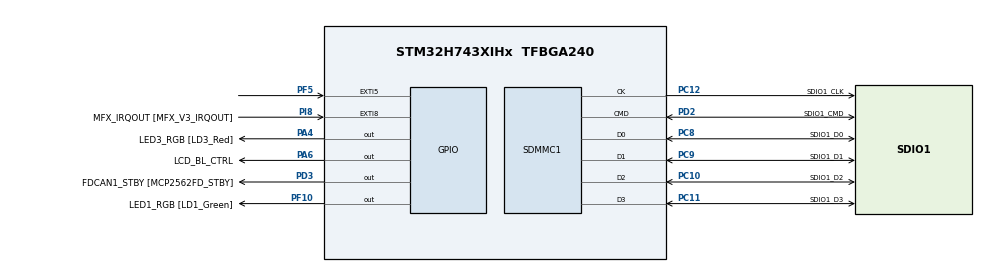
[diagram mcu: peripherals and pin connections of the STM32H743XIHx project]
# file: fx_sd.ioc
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CORTEX_M7.CPU_DCache=Enabled
CORTEX_M7.CPU_ICache=Enabled
CORTEX_M7.default_mode_Activation=1
Mcu.Family=STM32H7
Mcu.Name=STM32H743XIHx
Mcu.Package=TFBGA240
NVIC.EXTI9_5_IRQn=true\:6\:0\:true\:false\:true\:false\:true\:true\:true
NVIC.PriorityGroup=NVIC_PRIORITYGROUP_4
NVIC.SDMMC1_IRQn=true\:7\:0\:true\:false\:true\:false\:true\:true\:true
NVIC.TIM6_DAC_IRQn=true\:15\:0\:false\:false\:true\:false\:false\:true\:true
NVIC.TimeBase=TIM6_DAC_IRQn
NVIC.TimeBaseIP=TIM6
PA0_C.GPIO_Label=Potentiometer
PA0_C.Signal=ADCx_INN1
PA1.GPIO_Label=RMII_REF_CLK [LAN8742A_REFCLK0]
PA1.Signal=ETH_REF_CLK
PA10.GPIO_Label=USB_FS1_ID
PA10.Signal=USB_OTG_FS_ID
PA11.GPIO_Label=USB_FS1_DM
PA11.Signal=USB_OTG_FS_DM
PA12.GPIO_Label=USB_FS1_DP
PA12.Signal=USB_OTG_FS_DP
PA13\ (JTMS/SWDIO).GPIO_Label=TMS_SWDIO
PA13\ (JTMS/SWDIO).Signal=DEBUG_JTMS-SWDIO
PA14\ (JTCK/SWCLK).GPIO_Label=TCK_SWCLK
PA14\ (JTCK/SWCLK).Signal=DEBUG_JTCK-SWCLK
PA15\ (JTDI).GPIO_Label=TDI
PA15\ (JTDI).Signal=DEBUG_JTDI
PA2.GPIO_Label=ETH_MDIO [LAN8742A_MDIO]
PA2.Signal=ETH_MDIO
PA3.GPIO_Label=ULPI_D0 [USB3320C_D0]
PA3.Signal=USB_OTG_HS_ULPI_D0
PA4.GPIO_Label=LED3_RGB [LD3_Red]
PA4.Signal=GPIO_Output
PA5.GPIO_Label=ULPI_CK  [USB3320C_CLKOUT]
PA5.Signal=USB_OTG_HS_ULPI_CK
PA6.GPIO_Label=LCD_BL_CTRL
PA6.Signal=GPIO_Output
PA7.GPIO_Label=RMII_CRS_DV [LAN8742A_CRS_DV]
PA7.Signal=ETH_CRS_DV
PA8.GPIO_Label=MCO
PA8.Signal=RCC_MCO_1
PA9.GPIO_Label=VBUS_FS1
PA9.Signal=USB_OTG_FS_VBUS
PB0.GPIO_Label=ULPI_D1 [USB3320C_D1]
PB0.Signal=USB_OTG_HS_ULPI_D1
PB1.GPIO_Label=ULPI_D2 [USB3320C_D2]
PB1.Signal=USB_OTG_HS_ULPI_D2
PB10.GPIO_Label=ULPI_D3 [USB3320C_D3]
PB10.Signal=USB_OTG_HS_ULPI_D3
PB11.GPIO_Label=ULPI_D4 [USB3320C_D4]
PB11.Signal=USB_OTG_HS_ULPI_D4
PB12.GPIO_Label=ULPI_D5 [USB3320C_D5]
PB12.Signal=USB_OTG_HS_ULPI_D5
PB13.GPIO_Label=ULPI_D6 [USB3320C_D6]
PB13.Signal=USB_OTG_HS_ULPI_D6
PB14.GPIO_Label=RS232_TX [ST3241EBPR_T2IN]
PB14.Signal=USART1_TX
PB15.GPIO_Label=RS_232RX [ST3241EBPR_R3OUT]
PB15.Signal=USART1_RX
PB2.GPIO_Label=QSPI_CLK [MT25TL01GHBA8ESF_CLK_1]
PB2.Signal=QUADSPI_CLK
PB3\ (JTDO/TRACESWO).GPIO_Label=TDO_SWO
PB3\ (JTDO/TRACESWO).Signal=DEBUG_JTDO-SWO
PB4\ (NJTRST).GPIO_Label=TRST
PB4\ (NJTRST).Signal=DEBUG_JTRST
PB5.GPIO_Label=ULPI_D7 [USB3320C_D7]
PB5.Signal=USB_OTG_HS_ULPI_D7
PB6.GPIO_Label=I2C1_SCL [STM32L152CCT6_I2C_SCL]
PB6.Signal=I2C1_SCL
PB7.GPIO_Label=I2C1_SDA [STM32L152CCT6_I2C_SDA]
PB7.Signal=I2C1_SDA
PB8.GPIO_Label=SDIO1_CKIN
PB8.Signal=SDMMC1_CKIN
PB9.GPIO_Label=SDIO1_CDIR
PB9.Signal=SDMMC1_CDIR
PC0.GPIO_Label=ULPI_STP [USB3320C_STP]
PC0.Signal=USB_OTG_HS_ULPI_STP
PC1.GPIO_Label=RMII_MDC [LAN8742A_MDC]
PC1.Signal=ETH_MDC
PC10.GPIO_Label=SDIO1_D2
PC10.Mode=SD_4_bits_Wide_bus
PC10.Signal=SDMMC1_D2
PC11.GPIO_Label=SDIO1_D3
PC11.Mode=SD_4_bits_Wide_bus
PC11.Signal=SDMMC1_D3
PC12.GPIO_Label=SDIO1_CLK
PC12.Mode=SD_4_bits_Wide_bus
PC12.Signal=SDMMC1_CK
PC13.GPIO_Label=TAMPER_KEY [B1]
PC13.Signal=RTC_TAMP1
PC14-OSC32_IN\ (OSC32_IN).Signal=RCC_OSC32_IN
PC15-OSC32_OUT\ (OSC32_OUT).Signal=RCC_OSC32_OUT
PC2.GPIO_Label=DFSDM_CLK
PC2.Signal=S_CKOUTDFSDM1
PC3.GPIO_Label=DFSM_DAT1
PC3.Signal=S_DATAIN1DFSDM1
PC4.GPIO_Label=RMII_RXD0 [LAN8742A_RXD0]
PC4.Signal=ETH_RXD0
PC5.GPIO_Label=RMII_RXD1 [LAN8742A_RXD1]
PC5.Signal=ETH_RXD1
PC6.GPIO_Label=SDIO1_D0DIR
PC6.Signal=SDMMC1_D0DIR
PC7.GPIO_Label=SDIO1_D123DIR
PC7.Signal=SDMMC1_D123DIR
PC8.GPIO_Label=SDIO1_D0
PC8.Mode=SD_4_bits_Wide_bus
PC8.Signal=SDMMC1_D0
PC9.GPIO_Label=SDIO1_D1
PC9.Mode=SD_4_bits_Wide_bus
PC9.Signal=SDMMC1_D1
PD0.GPIO_Label=D2 [IS42S32800G_DQ2]
PD0.Signal=FMC_D2_DA2
PD1.GPIO_Label=D3 [IS42S32800G_DQ3]
PD1.Signal=FMC_D3_DA3
PD10.GPIO_Label=D15 [IS42S32800G_DQ15]
PD10.Signal=FMC_D15_DA15
PD11.GPIO_Label=A16 [PC28F128M29EWLA_A16]
PD11.Signal=FMC_A16_CLE
PD12.GPIO_Label=A17 [PC28F128M29EWLA_A17]
PD12.Signal=FMC_A17_ALE
PD13.GPIO_Label=A18 [PC28F128M29EWLA_A18]
PD13.Signal=FMC_A18
PD14.GPIO_Label=D0 [IS42S32800G_DQ0]
PD14.Signal=FMC_D0_DA0
PD15.GPIO_Label=D1 [IS42S32800G_DQ1]
PD15.Signal=FMC_D1_DA1
PD2.GPIO_Label=SDIO1_CMD
PD2.Mode=SD_4_bits_Wide_bus
PD2.Signal=SDMMC1_CMD
PD3.GPIO_Label=FDCAN1_STBY [MCP2562FD_STBY]
PD3.Signal=GPIO_Output
PD4.GPIO_Label=FMC_NOE [IS61WV102416BLL_OE]
PD4.Signal=FMC_NOE
PD5.GPIO_Label=FMC_NWE [IS61WV102416BLL_WE]
PD5.Signal=FMC_NWE
PD6.GPIO_Label=FMC_NWAIT [PC28F128M29EWLA_RB]
PD6.Signal=FMC_NWAIT
PD7.GPIO_Label=FMC_NE1 [PC28F128M29EWLA_E]
PD7.Signal=FMC_NE1
PD8.GPIO_Label=D13 [IS42S32800G_DQ13]
PD8.Signal=FMC_D13_DA13
PD9.GPIO_Label=D14 [IS42S32800G_DQ14]
PD9.Signal=FMC_D14_DA14
PE0.GPIO_Label=FMC_NBL0 [IS42S32800G_DQM0]
PE0.Signal=FMC_NBL0
PE1.GPIO_Label=FMC_NBL1 [IS42S32800G_DQM1]
PE1.Signal=FMC_NBL1
PE10.GPIO_Label=D7 [IS42S32800G_DQ7]
PE10.Signal=FMC_D7_DA7
PE11.GPIO_Label=D8 [IS42S32800G_DQ8]
PE11.Signal=FMC_D8_DA8
PE12.GPIO_Label=D9 [IS42S32800G_DQ9]
PE12.Signal=FMC_D9_DA9
PE13.GPIO_Label=D10 [IS42S32800G_DQ10]
PE13.Signal=FMC_D10_DA10
PE14.GPIO_Label=D11 [IS42S32800G_DQ11]
PE14.Signal=FMC_D11_DA11
PE15.GPIO_Label=D12 [IS42S32800G_DQ12]
PE15.Signal=FMC_D12_DA12
PE2.GPIO_Label=PDM1_CLK
PE2.Signal=SAI4_CK1
PE3.GPIO_Label=SAI1_SDB [WM8994ECS_ADCDAT1]
PE3.Signal=SAI1_SD_B
PE4.GPIO_Label=SAI1_FSA [WM8994ECS_LRCLK1]
PE4.Signal=SAI1_FS_A
PE5.GPIO_Label=SAI1_SCKA [WM8994ECS_BCK1]
PE5.Signal=SAI1_SCK_A
PE6.GPIO_Label=SAI1_SDA [WM8994ECS_DACDAT1]
PE6.Signal=SAI1_SD_A
PE7.GPIO_Label=D4 [IS42S32800G_DQ4]
PE7.Signal=FMC_D4_DA4
PE8.GPIO_Label=D5 [IS42S32800G_DQ5]
PE8.Signal=FMC_D5_DA5
PE9.GPIO_Label=D6 [IS42S32800G_DQ6]
PE9.Signal=FMC_D6_DA6
PF0.GPIO_Label=A0 [PC28F128M29EWLA_A0]
PF0.Signal=FMC_A0
PF1.GPIO_Label=A1 [PC28F128M29EWLA_A1]
PF1.Signal=FMC_A1
PF10.GPIO_Label=LED1_RGB [LD1_Green]
PF10.Signal=GPIO_Output
PF11.GPIO_Label=SNDRAS [IS42S32800G_RAS]
PF11.Signal=FMC_SDNRAS
PF12.GPIO_Label=A6 [PC28F128M29EWLA_A6]
PF12.Signal=FMC_A6
PF13.GPIO_Label=A7 [PC28F128M29EWLA_A7]
PF13.Signal=FMC_A7
PF14.GPIO_Label=A8 [PC28F128M29EWLA_A8]
PF14.Signal=FMC_A8
PF15.GPIO_Label=A9 [PC28F128M29EWLA_A9]
PF15.Signal=FMC_A9
PF2.GPIO_Label=A2 [PC28F128M29EWLA_A2]
PF2.Signal=FMC_A2
PF3.GPIO_Label=A3 [PC28F128M29EWLA_A3]
PF3.Signal=FMC_A3
PF4.GPIO_Label=A4 [PC28F128M29EWLA_A4]
PF4.Signal=FMC_A4
PF5.Signal=GPXTI5
PF6.GPIO_Label=QSPI_BK1_IO3 [MT25TL01GHBA8ESF_DQ3]
PF6.Signal=QUADSPI_BK1_IO3
PF7.GPIO_Label=QSPI_BK1_IO2 [MT25TL01GHBA8ESF_DQ2]
PF7.Signal=QUADSPI_BK1_IO2
PF8.GPIO_Label=QSPI_BK1_IO0 [MT25TL01GHBA8ESF_DQ0]
PF8.Signal=QUADSPI_BK1_IO0
PF9.GPIO_Label=QSPI_BK1_IO1 [MT25TL01GHBA8ESF_DQ1]
PF9.Signal=QUADSPI_BK1_IO1
PG0.GPIO_Label=A10 [PC28F128M29EWLA_A10]
PG0.Signal=FMC_A10
PG1.GPIO_Label=A11 [PC28F128M29EWLA_A11]
PG1.Signal=FMC_A11
PG10.GPIO_Label=FMC_NE3 [IS61WV102416BLL_CE]
PG10.Signal=FMC_NE3
PG11.GPIO_Label=RMII_TX_EN [LAN8742A_TXEN]
PG11.Signal=ETH_TX_EN
PG12.GPIO_Label=RMII_TXD1 [LAN8742A_TXD1]
PG12.Signal=ETH_TXD1
PG13.GPIO_Label=RMII_TXD0 [LAN8742A_TXD0]
PG13.Signal=ETH_TXD0
PG14.GPIO_Label=QSPI_BK2_IO3 [MT25TL01GHBA8ESF_DQ7]
PG14.Signal=QUADSPI_BK2_IO3
PG15.GPIO_Label=SDNCAS [IS42S32800G_CAS]
PG15.Signal=FMC_SDNCAS
PG2.GPIO_Label=A12 [PC28F128M29EWLA_A12]
PG2.Signal=FMC_A12
PG3.GPIO_Label=A13 [PC28F128M29EWLA_A13]
PG3.Signal=FMC_A13
PG4.Signal=FMC_A14_BA0
PG5.Signal=FMC_A15_BA1
PG6.GPIO_Label=QSPI_BK1_NCS [MT25TL01GHBA8ESF_CS]
PG6.Signal=QUADSPI_BK1_NCS
PG7.GPIO_Label=SAI1_MCLKA [WM8994ECS_MCLK1]
PG7.Signal=SAI1_MCLK_A
PG8.GPIO_Label=SDCLK [IS42S32800G_CLK]
PG8.Signal=FMC_SDCLK
PG9.GPIO_Label=QSPI_BK2_IO2 [MT25TL01GHBA8ESF_DQ6]
PG9.Signal=QUADSPI_BK2_IO2
PH0-OSC_IN\ (PH0).Mode=HSE-External-Oscillator
PH0-OSC_IN\ (PH0).Signal=RCC_OSC_IN
PH1-OSC_OUT\ (PH1).Mode=HSE-External-Oscillator
PH1-OSC_OUT\ (PH1).Signal=RCC_OSC_OUT
PH10.GPIO_Label=D18 [IS42S32800G_DQ18]
PH10.Signal=FMC_D18
PH11.GPIO_Label=D19 [IS42S32800G_DQ19]
PH11.Signal=FMC_D19
PH12.GPIO_Label=D20 [IS42S32800G_DQ20]
PH12.Signal=FMC_D20
PH13.GPIO_Label=D21 [IS42S32800G_DQ21]
PH13.Signal=FMC_D21
PH14.GPIO_Label=D22 [IS42S32800G_DQ22]
PH14.Signal=FMC_D22
PH15.GPIO_Label=D23 [IS42S32800G_DQ23]
PH15.Signal=FMC_D23
PH2.GPIO_Label=QSPI_BK2_IO0 [MT25TL01GHBA8ESF_DQ4]
PH2.Signal=QUADSPI_BK2_IO0
PH3.GPIO_Label=QSPI_BK2_IO1 [MT25TL01GHBA8ESF_DQ5]
PH3.Signal=QUADSPI_BK2_IO1
PH4.GPIO_Label=ULPI_NXT [USB3320C_NXT]
PH4.Signal=USB_OTG_HS_ULPI_NXT
PH5.GPIO_Label=SDNWE [IS42S32800G_WE]
PH5.Signal=FMC_SDNWE
PH6.GPIO_Label=SDNE1 [IS42S32800G_CS]
PH6.Signal=FMC_SDNE1
PH7.GPIO_Label=SDCKE1 [IS42S32800G_CKE]
PH7.Signal=FMC_SDCKE1
PH8.GPIO_Label=D16 [IS42S32800G_DQ16]
PH8.Signal=FMC_D16
PH9.GPIO_Label=D17 [IS42S32800G_DQ17]
PH9.Signal=FMC_D17
PI0.GPIO_Label=D24 [IS42S32800G_DQ24]
PI0.Signal=FMC_D24
PI1.GPIO_Label=D25 [IS42S32800G_DQ25]
PI1.Signal=FMC_D25
PI10.GPIO_Label=D31 [IS42S32800G_DQ31]
PI10.Signal=FMC_D31
PI11.GPIO_Label=ULPI_DIR [USB3320C_DIR]
PI11.Signal=USB_OTG_HS_ULPI_DIR
PI12.GPIO_Label=LCD_HSYNC
PI12.Signal=LTDC_HSYNC
PI13.GPIO_Label=LCD_VSYNC
PI13.Signal=LTDC_VSYNC
PI14.GPIO_Label=LCD_CLK
PI14.Signal=LTDC_CLK
PI15.GPIO_Label=LCD_R0
PI15.Signal=LTDC_R0
PI2.GPIO_Label=D26 [IS42S32800G_DQ26]
PI2.Signal=FMC_D26
PI3.GPIO_Label=D27 [IS42S32800G_DQ27
PI3.Signal=FMC_D27
PI4.GPIO_Label=FMC_NBL2 [IS42S32800G_DQM2]
PI4.Signal=FMC_NBL2
PI5.GPIO_Label=FMC_NBL3 [IS42S32800G_DQM3]
PI5.Signal=FMC_NBL3
PI6.GPIO_Label=D28 [IS42S32800G_DQ28]
PI6.Signal=FMC_D28
PI7.GPIO_Label=D29 [IS42S32800G_DQ29]
PI7.Signal=FMC_D29
PI8.GPIO_Label=MFX_IRQOUT [MFX_V3_IRQOUT]
PI8.Signal=GPXTI8
PI9.GPIO_Label=D30 [IS42S32800G_DQ30]
PI9.Signal=FMC_D30
PJ0.GPIO_Label=LCD_R1
PJ0.Signal=LTDC_R1
PJ1.GPIO_Label=LCD_R2
PJ1.Signal=LTDC_R2
PJ10.GPIO_Label=LCd_G3
PJ10.Signal=LTDC_G3
PJ11.GPIO_Label=LCD_G4
PJ11.Signal=LTDC_G4
PJ12.GPIO_Label=LCD_B0
PJ12.Signal=LTDC_B0
PJ13.GPIO_Label=LCD_B1
PJ13.Signal=LTDC_B1
PJ14.GPIO_Label=LCD_B2
PJ14.Signal=LTDC_B2
PJ15.GPIO_Label=LCD_B3
PJ15.Signal=LTDC_B3
PJ2.GPIO_Label=LCD_R3
PJ2.Signal=LTDC_R3
PJ3.GPIO_Label=LCD_R4
PJ3.Signal=LTDC_R4
PJ4.GPIO_Label=LCD_R5
PJ4.Signal=LTDC_R5
PJ5.GPIO_Label=LCD_R6
PJ5.Signal=LTDC_R6
PJ6.GPIO_Label=LCD_R7
PJ6.Signal=LTDC_R7
PJ7.GPIO_Label=LCD_G0
PJ7.Signal=LTDC_G0
PJ8.GPIO_Label=LCD_G1
PJ8.Signal=LTDC_G1
PJ9.GPIO_Label=LCD_G2
PJ9.Signal=LTDC_G2
PK0.GPIO_Label=LCD_G5
PK0.Signal=LTDC_G5
PK1.GPIO_Label=LCD_G6
PK1.Signal=LTDC_G6
PK2.GPIO_Label=LCD_G7
PK2.Signal=LTDC_G7
PK3.GPIO_Label=LCD_B4
PK3.Signal=LTDC_B4
PK4.GPIO_Label=LCD_B5
PK4.Signal=LTDC_B5
PK5.GPIO_Label=LCD_B6
PK5.Signal=LTDC_B6
PK6.GPIO_Label=LCD_B7
PK6.Signal=LTDC_B7
PK7.GPIO_Label=LCD_DE
PK7.Signal=LTDC_DE
ProjectManager.HeapSize=0x200
ProjectManager.StackSize=0x400
ProjectManager.TargetToolchain=STM32CubeIDE
RCC.ADCFreq_Value=50390625
RCC.APB1Freq_Value=100000000
RCC.APB2Freq_Value=100000000
RCC.APB3Freq_Value=100000000
RCC.APB4Freq_Value=100000000
RCC.CortexFreq_Value=400000000
RCC.D1PPRE=RCC_APB3_DIV2
RCC.D2PPRE1=RCC_APB1_DIV2
RCC.D2PPRE2=RCC_APB2_DIV2
RCC.D3PPRE=RCC_APB4_DIV2
RCC.DIVM1=5
RCC.DIVN1=160
RCC.DIVN3=160
RCC.DIVQ1=4
RCC.HCLKFreq_Value=200000000
RCC.HPRE=RCC_HCLK_DIV2
RCC.PLL2FRACN=0
RCC.PLL3FRACN=0
RCC.PLLFRACN=0
RCC.PLLSourceVirtual=RCC_PLLSOURCE_HSE
RCC.PWR_Regulator_Voltage_Scale=PWR_REGULATOR_VOLTAGE_SCALE1
RCC.SDMMC1CLockSelection=RCC_SDMMCCLKSOURCE_PLL2
RCC.SYSCLKFreq_VALUE=400000000
RCC.SYSCLKSource=RCC_SYSCLKSOURCE_PLLCLK
RCC.USBFreq_Value=200000000
SH.ADCx_INN1.0=ADC1_INN1
SH.FMC_A0.0=FMC_A0
SH.FMC_A1.0=FMC_A1
SH.FMC_A10.0=FMC_A10
SH.FMC_A11.0=FMC_A11
SH.FMC_A12.0=FMC_A12
SH.FMC_A13.0=FMC_A13
SH.FMC_A14_BA0.0=FMC_BA0
SH.FMC_A14_BA0.1=FMC_A14
SH.FMC_A15_BA1.0=FMC_BA1
SH.FMC_A15_BA1.1=FMC_A15
SH.FMC_A16_CLE.0=FMC_A16
SH.FMC_A17_ALE.0=FMC_A17
SH.FMC_A18.0=FMC_A18
SH.FMC_A2.0=FMC_A2
SH.FMC_A3.0=FMC_A3
SH.FMC_A4.0=FMC_A4
SH.FMC_A6.0=FMC_A6
SH.FMC_A7.0=FMC_A7
SH.FMC_A8.0=FMC_A8
SH.FMC_A9.0=FMC_A9
SH.FMC_D0_DA0.0=FMC_D0
SH.FMC_D10_DA10.0=FMC_D10
SH.FMC_D11_DA11.0=FMC_D11
SH.FMC_D12_DA12.0=FMC_D12
SH.FMC_D13_DA13.0=FMC_D13
SH.FMC_D14_DA14.0=FMC_D14
SH.FMC_D15_DA15.0=FMC_D15
SH.FMC_D16.0=FMC_D16
SH.FMC_D17.0=FMC_D17
SH.FMC_D18.0=FMC_D18
SH.FMC_D19.0=FMC_D19
SH.FMC_D1_DA1.0=FMC_D1
SH.FMC_D20.0=FMC_D20
SH.FMC_D21.0=FMC_D21
SH.FMC_D22.0=FMC_D22
SH.FMC_D23.0=FMC_D23
SH.FMC_D24.0=FMC_D24
SH.FMC_D25.0=FMC_D25
SH.FMC_D26.0=FMC_D26
SH.FMC_D27.0=FMC_D27
SH.FMC_D28.0=FMC_D28
SH.FMC_D29.0=FMC_D29
SH.FMC_D2_DA2.0=FMC_D2
SH.FMC_D30.0=FMC_D30
SH.FMC_D31.0=FMC_D31
SH.FMC_D3_DA3.0=FMC_D3
SH.FMC_D4_DA4.0=FMC_D4
SH.FMC_D5_DA5.0=FMC_D5
SH.FMC_D6_DA6.0=FMC_D6
SH.FMC_D7_DA7.0=FMC_D7
SH.FMC_D8_DA8.0=FMC_D8
SH.FMC_D9_DA9.0=FMC_D9
SH.FMC_NBL0.0=FMC_NBL0
SH.FMC_NBL1.0=FMC_NBL1
SH.FMC_NBL2.0=FMC_NBL2
SH.FMC_NBL3.0=FMC_NBL3
SH.FMC_NOE.0=FMC_NOE
SH.FMC_NWAIT.0=FMC_NWAIT
SH.FMC_NWE.0=FMC_NWE
SH.FMC_SDCLK.0=FMC_SDCLK
SH.FMC_SDNCAS.0=FMC_SDNCAS
SH.FMC_SDNRAS.0=FMC_SDNRAS
SH.FMC_SDNWE.0=FMC_SDNWE
SH.S_CKOUTDFSDM1.0=DFSDM1_CKOUT
SH.S_DATAIN1DFSDM1.0=DFSDM1_DATIN1
STMicroelectronics.X-CUBE-AZRTOS-H7.3.2.0.FX_DRIVER_SD_INIT=1
STMicroelectronics.X-CUBE-AZRTOS-H7.3.2.0.FileXCcFileOoSystemJjFileXJjCore=true
STMicroelectronics.X-CUBE-AZRTOS-H7.3.2.0.InterfacesCcFileOoSystemJjFileXOoSDOointerface=true
STMicroelectronics.X-CUBE-AZRTOS-H7.3.2.0.ThreadXCcRTOSJjThreadXJjCore=true
STMicroelectronics.X-CUBE-AZRTOS-H7.3.2.0_IsAnAzureRtosMw=true
VP_STMicroelectronics.X-CUBE-AZRTOS-H7_VS_FileOoSystemJjFileX_6.2.1_3.2.0.Mode=FileOoSystemJjFileX
VP_STMicroelectronics.X-CUBE-AZRTOS-H7_VS_FileOoSystemJjInterfaces_3.2.0_3.2.0.Mode=FileOoSystemJjInterfaces
VP_STMicroelectronics.X-CUBE-AZRTOS-H7_VS_RTOSJjThreadX_6.2.1_3.2.0.Mode=RTOSJjThreadX
VP_SYS_VS_tim6.Mode=TIM6
board=STM32H743I-EVAL2

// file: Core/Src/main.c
/* USER CODE BEGIN Header */
/**
  ******************************************************************************
  * @file           : main.c
  * @brief          : Main program body
  ******************************************************************************
  * @attention
  *
  * Copyright (c) 2024 STMicroelectronics.
  * All rights reserved.
  *
  * This software is licensed under terms that can be found in the LICENSE file
  * in the root directory of this software component.
  * If no LICENSE file comes with this software, it is provided AS-IS.
  *
  ******************************************************************************
  */
/* USER CODE END Header */
#include "app_threadx.h"
#include "main.h"

SD_HandleTypeDef hsd1;

void SystemClock_Config(void);
//static void MPU_Initialize(void);
static void MPU_Config(void);
static void MX_GPIO_Init(void);

int main(void)
{

  /* Enable I-Cache---------------------------------------------------------*/
  SCB_EnableICache();

  /* Enable D-Cache---------------------------------------------------------*/
  SCB_EnableDCache();

  /* MCU Configuration--------------------------------------------------------*/

  /* Reset of all peripherals, Initializes the Flash interface and the Systick. */
  HAL_Init();

  /* MPU Configuration--------------------------------------------------------*/
  MPU_Config();

  /* Configure the system clock */
  SystemClock_Config();

  /* Initialize all configured peripherals */
  MX_GPIO_Init();
  MX_SDMMC1_SD_Init();

  MX_ThreadX_Init();

  /* We should never get here as control is now taken by the scheduler */
  /* Infinite loop */
  while (1)
  {

  }
}

void SystemClock_Config(void)
{
	RCC_ClkInitTypeDef RCC_ClkInitStruct;
	  RCC_OscInitTypeDef RCC_OscInitStruct;
	  RCC_PeriphCLKInitTypeDef RCC_PeriphCLKInitStruct;
	  HAL_StatusTypeDef ret = HAL_OK;

	  /*!< Supply configuration update enable */
	  HAL_PWREx_ConfigSupply(PWR_LDO_SUPPLY);

	  /* The voltage scaling allows optimizing the power consumption when the device is
	     clocked below the maximum system frequency, to update the voltage scaling value
	     regarding system frequency refer to product datasheet.  */
	  __HAL_PWR_VOLTAGESCALING_CONFIG(PWR_REGULATOR_VOLTAGE_SCALE1);

	  while(!__HAL_PWR_GET_FLAG(PWR_FLAG_VOSRDY)) {}

	  /* Enable HSE Oscillator and activate PLL with HSE as source */
	  RCC_OscInitStruct.OscillatorType = RCC_OSCILLATORTYPE_HSE;
	  RCC_OscInitStruct.HSEState = RCC_HSE_ON;
	  RCC_OscInitStruct.HSIState = RCC_HSI_OFF;
	  RCC_OscInitStruct.CSIState = RCC_CSI_OFF;
	  RCC_OscInitStruct.PLL.PLLState = RCC_PLL_ON;
	  RCC_OscInitStruct.PLL.PLLSource = RCC_PLLSOURCE_HSE;

	  RCC_OscInitStruct.PLL.PLLM = 5;
	  RCC_OscInitStruct.PLL.PLLN = 160;
	  RCC_OscInitStruct.PLL.PLLFRACN = 0;
	  RCC_OscInitStruct.PLL.PLLP = 2;
	  RCC_OscInitStruct.PLL.PLLR = 2;
	  RCC_OscInitStruct.PLL.PLLQ = 4;

	  RCC_OscInitStruct.PLL.PLLVCOSEL = RCC_PLL1VCOWIDE;
	  RCC_OscInitStruct.PLL.PLLRGE = RCC_PLL1VCIRANGE_2;
	  ret = HAL_RCC_OscConfig(&RCC_OscInitStruct);
	  if(ret != HAL_OK)
	  {
	    Error_Handler();
	  }

	/* Select PLL as system clock source and configure  bus clocks dividers */
	  RCC_ClkInitStruct.ClockType = (RCC_CLOCKTYPE_SYSCLK | RCC_CLOCKTYPE_HCLK | RCC_CLOCKTYPE_D1PCLK1 | RCC_CLOCKTYPE_PCLK1 | \
	                                  RCC_CLOCKTYPE_PCLK2  | RCC_CLOCKTYPE_D3PCLK1);

	  RCC_ClkInitStruct.SYSCLKSource = RCC_SYSCLKSOURCE_PLLCLK;
	  RCC_ClkInitStruct.SYSCLKDivider = RCC_SYSCLK_DIV1;
	  RCC_ClkInitStruct.AHBCLKDivider = RCC_HCLK_DIV2;
	  RCC_ClkInitStruct.APB3CLKDivider = RCC_APB3_DIV2;
	  RCC_ClkInitStruct.APB1CLKDivider = RCC_APB1_DIV2;
	  RCC_ClkInitStruct.APB2CLKDivider = RCC_APB2_DIV2;
	  RCC_ClkInitStruct.APB4CLKDivider = RCC_APB4_DIV2;
	  ret = HAL_RCC_ClockConfig(&RCC_ClkInitStruct, FLASH_LATENCY_4);
	  if(ret != HAL_OK)
	  {
	    Error_Handler();
	  }

	  /* PLL2_VCO Input = HSE_VALUE/PLL2_M = 5 Mhz */
	  /* PLL2_VCO Output = PLL2_VCO Input * PLL_N = 700 Mhz */
	  /* SDMMC Kernel Clock = PLL2_VCO Output/PLL_R = 700/6 = 116 Mhz */
	  RCC_PeriphCLKInitStruct.PeriphClockSelection = RCC_PERIPHCLK_SDMMC;
	  RCC_PeriphCLKInitStruct.SdmmcClockSelection = RCC_SDMMCCLKSOURCE_PLL2;
	  RCC_PeriphCLKInitStruct.PLL2.PLL2RGE = RCC_PLL1VCIRANGE_2;
	  RCC_PeriphCLKInitStruct.PLL2.PLL2M = 5;
	  RCC_PeriphCLKInitStruct.PLL2.PLL2N = 140;
	  RCC_PeriphCLKInitStruct.PLL2.PLL2FRACN = 0;
	  RCC_PeriphCLKInitStruct.PLL2.PLL2P = 2;
	  RCC_PeriphCLKInitStruct.PLL2.PLL2R = 6;
	  RCC_PeriphCLKInitStruct.PLL2.PLL2Q = 4;
	  RCC_PeriphCLKInitStruct.PLL2.PLL2VCOSEL = RCC_PLL2VCOWIDE;
	  ret = HAL_RCCEx_PeriphCLKConfig(&RCC_PeriphCLKInitStruct);
	  if(ret != HAL_OK)
	  {
	    Error_Handler();
	  }

	  /*activate CSI clock mondatory for I/O Compensation Cell*/
	  __HAL_RCC_CSI_ENABLE() ;

	  /* Enable SYSCFG clock mondatory for I/O Compensation Cell */
	  __HAL_RCC_SYSCFG_CLK_ENABLE() ;

	  /* Enables the I/O Compensation Cell */
	  HAL_EnableCompensationCell();

}

 void MX_SDMMC1_SD_Init(void)
{

  hsd1.Instance = SDMMC1;

  hsd1.Init.ClockEdge = SDMMC_CLOCK_EDGE_RISING;
  hsd1.Init.ClockPowerSave = SDMMC_CLOCK_POWER_SAVE_DISABLE;
  hsd1.Init.BusWide = SDMMC_BUS_WIDE_1B;
  hsd1.Init.HardwareFlowControl = SDMMC_HARDWARE_FLOW_CONTROL_DISABLE;
  hsd1.Init.ClockDiv = 0;
 // hsd1.Init.TranceiverPresent = SDMMC_TRANSCEIVER_PRESENT;
  if (HAL_SD_Init(&hsd1) != HAL_OK)
  {
    Error_Handler();
  }

}

static void MX_GPIO_Init(void)
{
  GPIO_InitTypeDef GPIO_InitStruct = {0};

  /* GPIO Ports Clock Enable */
  __HAL_RCC_GPIOI_CLK_ENABLE();
  __HAL_RCC_GPIOB_CLK_ENABLE();
  __HAL_RCC_GPIOK_CLK_ENABLE();
  __HAL_RCC_GPIOG_CLK_ENABLE();
  __HAL_RCC_GPIOD_CLK_ENABLE();
  __HAL_RCC_GPIOC_CLK_ENABLE();
  __HAL_RCC_GPIOA_CLK_ENABLE();
  __HAL_RCC_GPIOE_CLK_ENABLE();
  __HAL_RCC_GPIOJ_CLK_ENABLE();
  __HAL_RCC_GPIOH_CLK_ENABLE();
  __HAL_RCC_GPIOF_CLK_ENABLE();

  /*Configure GPIO pin Output Level */
  HAL_GPIO_WritePin(FDCAN1_STBY_GPIO_Port, FDCAN1_STBY_Pin, GPIO_PIN_RESET);

  /*Configure GPIO pin Output Level */
  HAL_GPIO_WritePin(LED1_GPIO_Port, LED1_Pin, GPIO_PIN_SET);

  /*Configure GPIO pin Output Level */

  /*Configure GPIO pins : D28_Pin FMC_NBL3_Pin FMC_NBL2_Pin D25_Pin
                           D24_Pin D29_Pin D26_Pin D27__IS42S32800G_DQ27_Pin
                           D30_Pin D31_Pin */
  GPIO_InitStruct.Pin = D28_Pin|FMC_NBL3_Pin|FMC_NBL2_Pin|D25_Pin
                          |D24_Pin|D29_Pin|D26_Pin|D27__IS42S32800G_DQ27_Pin
                          |D30_Pin|D31_Pin;
  GPIO_InitStruct.Mode = GPIO_MODE_AF_PP;
  GPIO_InitStruct.Pull = GPIO_NOPULL;
  GPIO_InitStruct.Speed = GPIO_SPEED_FREQ_VERY_HIGH;
  GPIO_InitStruct.Alternate = GPIO_AF12_FMC;
  HAL_GPIO_Init(GPIOI, &GPIO_InitStruct);

  /*Configure GPIO pins : ULPI_D7_Pin ULPI_D3_Pin ULPI_D4_Pin ULPI_D2_Pin
                           ULPI_D5_Pin ULPI_D1_Pin ULPI_D6_Pin */
  GPIO_InitStruct.Pin = ULPI_D7_Pin|ULPI_D3_Pin|ULPI_D4_Pin|ULPI_D2_Pin
                          |ULPI_D5_Pin|ULPI_D1_Pin|ULPI_D6_Pin;
  GPIO_InitStruct.Mode = GPIO_MODE_AF_PP;
  GPIO_InitStruct.Pull = GPIO_NOPULL;
  GPIO_InitStruct.Speed = GPIO_SPEED_FREQ_HIGH;
  GPIO_InitStruct.Alternate = GPIO_AF10_OTG2_HS;
  HAL_GPIO_Init(GPIOB, &GPIO_InitStruct);

  /*Configure GPIO pins : LCD_B6_Pin LCD_B5_Pin LCD_B7_Pin LCD_B4_Pin
                           LCD_DE_Pin LCD_G7_Pin LCD_G5_Pin LCD_G6_Pin */
  GPIO_InitStruct.Pin = LCD_B6_Pin|LCD_B5_Pin|LCD_B7_Pin|LCD_B4_Pin
                          |LCD_DE_Pin|LCD_G7_Pin|LCD_G5_Pin|LCD_G6_Pin;
  GPIO_InitStruct.Mode = GPIO_MODE_AF_PP;
  GPIO_InitStruct.Pull = GPIO_NOPULL;
  GPIO_InitStruct.Speed = GPIO_SPEED_FREQ_LOW;
  GPIO_InitStruct.Alternate = GPIO_AF14_LTDC;
  HAL_GPIO_Init(GPIOK, &GPIO_InitStruct);

  /*Configure GPIO pins : FMC_NE3_Pin SDNCAS_Pin SDCLK_Pin PG5
                           PG4 A13_Pin A12_Pin A10_Pin
                           A11_Pin */
  GPIO_InitStruct.Pin = FMC_NE3_Pin|SDNCAS_Pin|SDCLK_Pin|GPIO_PIN_5
                          |GPIO_PIN_4|A13_Pin|A12_Pin|A10_Pin
                          |A11_Pin;
  GPIO_InitStruct.Mode = GPIO_MODE_AF_PP;
  GPIO_InitStruct.Pull = GPIO_NOPULL;
  GPIO_InitStruct.Speed = GPIO_SPEED_FREQ_VERY_HIGH;
  GPIO_InitStruct.Alternate = GPIO_AF12_FMC;
  HAL_GPIO_Init(GPIOG, &GPIO_InitStruct);

  /*Configure GPIO pins : QSPI_BK2_IO2_Pin QSPI_BK2_IO3_Pin */
  GPIO_InitStruct.Pin = QSPI_BK2_IO2_Pin|QSPI_BK2_IO3_Pin;
  GPIO_InitStruct.Mode = GPIO_MODE_AF_PP;
  GPIO_InitStruct.Pull = GPIO_NOPULL;
  GPIO_InitStruct.Speed = GPIO_SPEED_FREQ_LOW;
  GPIO_InitStruct.Alternate = GPIO_AF9_QUADSPI;
  HAL_GPIO_Init(GPIOG, &GPIO_InitStruct);

  /*Configure GPIO pins : FMC_NWE_Pin FMC_NOE_Pin FMC_NWAIT_Pin FMC_NE1_Pin
                           D2_Pin D3_Pin D1_Pin D0_Pin
                           A16_Pin A17_Pin A18_Pin D15_Pin
                           D14_Pin D13_Pin */
  GPIO_InitStruct.Pin = FMC_NWE_Pin|FMC_NOE_Pin|FMC_NWAIT_Pin|FMC_NE1_Pin
                          |D2_Pin|D3_Pin|D1_Pin|D0_Pin
                          |A16_Pin|A17_Pin|A18_Pin|D15_Pin
                          |D14_Pin|D13_Pin;
  GPIO_InitStruct.Mode = GPIO_MODE_AF_PP;
  GPIO_InitStruct.Pull = GPIO_NOPULL;
  GPIO_InitStruct.Speed = GPIO_SPEED_FREQ_VERY_HIGH;
  GPIO_InitStruct.Alternate = GPIO_AF12_FMC;
  HAL_GPIO_Init(GPIOD, &GPIO_InitStruct);

  /*Configure GPIO pins : FMC_NBL1_Pin FMC_NBL0_Pin D7_Pin D6_Pin
                           D8_Pin D9_Pin D12_Pin D5_Pin
                           D10_Pin D4_Pin D11_Pin */
  GPIO_InitStruct.Pin = FMC_NBL1_Pin|FMC_NBL0_Pin|D7_Pin|D6_Pin
                          |D8_Pin|D9_Pin|D12_Pin|D5_Pin
                          |D10_Pin|D4_Pin|D11_Pin;
  GPIO_InitStruct.Mode = GPIO_MODE_AF_PP;
  GPIO_InitStruct.Pull = GPIO_NOPULL;
  GPIO_InitStruct.Speed = GPIO_SPEED_FREQ_VERY_HIGH;
  GPIO_InitStruct.Alternate = GPIO_AF12_FMC;
  HAL_GPIO_Init(GPIOE, &GPIO_InitStruct);

  /*Configure GPIO pins : I2C1_SCL_Pin I2C1_SDA_Pin */
  GPIO_InitStruct.Pin = I2C1_SCL_Pin|I2C1_SDA_Pin;
  GPIO_InitStruct.Mode = GPIO_MODE_AF_OD;
  GPIO_InitStruct.Pull = GPIO_NOPULL;
  GPIO_InitStruct.Speed = GPIO_SPEED_FREQ_LOW;
  GPIO_InitStruct.Alternate = GPIO_AF4_I2C1;
  HAL_GPIO_Init(GPIOB, &GPIO_InitStruct);

  /*Configure GPIO pins : RMII_TX_EN_Pin RMII_TXD1_Pin RMII_TXD0_Pin */
  GPIO_InitStruct.Pin = RMII_TX_EN_Pin|RMII_TXD1_Pin|RMII_TXD0_Pin;
  GPIO_InitStruct.Mode = GPIO_MODE_AF_PP;
  GPIO_InitStruct.Pull = GPIO_NOPULL;
  GPIO_InitStruct.Speed = GPIO_SPEED_FREQ_LOW;
  GPIO_InitStruct.Alternate = GPIO_AF11_ETH;
  HAL_GPIO_Init(GPIOG, &GPIO_InitStruct);

  /*Configure GPIO pins : LCD_B3_Pin LCD_B2_Pin LCD_B0_Pin LCD_B1_Pin
                           LCD_G4_Pin LCd_G3_Pin LCD_G2_Pin LCD_R1_Pin
                           LCD_G1_Pin LCD_G0_Pin LCD_R7_Pin LCD_R2_Pin
                           LCD_R6_Pin LCD_R3_Pin LCD_R4_Pin LCD_R5_Pin */
  GPIO_InitStruct.Pin = LCD_B3_Pin|LCD_B2_Pin|LCD_B0_Pin|LCD_B1_Pin
                          |LCD_G4_Pin|LCd_G3_Pin|LCD_G2_Pin|LCD_R1_Pin
                          |LCD_G1_Pin|LCD_G0_Pin|LCD_R7_Pin|LCD_R2_Pin
                          |LCD_R6_Pin|LCD_R3_Pin|LCD_R4_Pin|LCD_R5_Pin;
  GPIO_InitStruct.Mode = GPIO_MODE_AF_PP;
  GPIO_InitStruct.Pull = GPIO_NOPULL;
  GPIO_InitStruct.Speed = GPIO_SPEED_FREQ_LOW;
  GPIO_InitStruct.Alternate = GPIO_AF14_LTDC;
  HAL_GPIO_Init(GPIOJ, &GPIO_InitStruct);

  /*Configure GPIO pin : FDCAN1_STBY_Pin */
  GPIO_InitStruct.Pin = FDCAN1_STBY_Pin;
  GPIO_InitStruct.Mode = GPIO_MODE_OUTPUT_PP;
  GPIO_InitStruct.Pull = GPIO_NOPULL;
  GPIO_InitStruct.Speed = GPIO_SPEED_FREQ_LOW;
  HAL_GPIO_Init(FDCAN1_STBY_GPIO_Port, &GPIO_InitStruct);

  /*Configure GPIO pins : D23_Pin D22_Pin D21_Pin SDNWE_Pin
                           D18_Pin D19_Pin D17_Pin D20_Pin
                           SDNE1_Pin D16_Pin SDCKE1_Pin */
  GPIO_InitStruct.Pin = D23_Pin|D22_Pin|D21_Pin|SDNWE_Pin
                          |D18_Pin|D19_Pin|D17_Pin|D20_Pin
                          |SDNE1_Pin|D16_Pin|SDCKE1_Pin;
  GPIO_InitStruct.Mode = GPIO_MODE_AF_PP;
  GPIO_InitStruct.Pull = GPIO_NOPULL;
  GPIO_InitStruct.Speed = GPIO_SPEED_FREQ_VERY_HIGH;
  GPIO_InitStruct.Alternate = GPIO_AF12_FMC;
  HAL_GPIO_Init(GPIOH, &GPIO_InitStruct);

  /*Configure GPIO pin : PDM1_CLK_Pin */
  GPIO_InitStruct.Pin = PDM1_CLK_Pin;
  GPIO_InitStruct.Mode = GPIO_MODE_AF_PP;
  GPIO_InitStruct.Pull = GPIO_NOPULL;
  GPIO_InitStruct.Speed = GPIO_SPEED_FREQ_LOW;
  GPIO_InitStruct.Alternate = GPIO_AF10_SAI4;
  HAL_GPIO_Init(PDM1_CLK_GPIO_Port, &GPIO_InitStruct);

  /*Configure GPIO pins : SAI1_SCKA_Pin SAI1_FSA_Pin SAI1_SDB_Pin SAI1_SDA_Pin */
  GPIO_InitStruct.Pin = SAI1_SCKA_Pin|SAI1_FSA_Pin|SAI1_SDB_Pin|SAI1_SDA_Pin;
  GPIO_InitStruct.Mode = GPIO_MODE_AF_PP;
  GPIO_InitStruct.Pull = GPIO_NOPULL;
  GPIO_InitStruct.Speed = GPIO_SPEED_FREQ_LOW;
  GPIO_InitStruct.Alternate = GPIO_AF6_SAI1;
  HAL_GPIO_Init(GPIOE, &GPIO_InitStruct);

  /*Configure GPIO pins : USB_FS1_ID_Pin USB_FS1_DP_Pin USB_FS1_DM_Pin */
  GPIO_InitStruct.Pin = USB_FS1_ID_Pin|USB_FS1_DP_Pin|USB_FS1_DM_Pin;
  GPIO_InitStruct.Mode = GPIO_MODE_AF_PP;
  GPIO_InitStruct.Pull = GPIO_NOPULL;
  GPIO_InitStruct.Speed = GPIO_SPEED_FREQ_LOW;
  GPIO_InitStruct.Alternate = GPIO_AF10_OTG1_FS;
  HAL_GPIO_Init(GPIOA, &GPIO_InitStruct);

  /*Configure GPIO pin : MFX_IRQOUT_Pin */
  GPIO_InitStruct.Pin = MFX_IRQOUT_Pin;
  GPIO_InitStruct.Mode = GPIO_MODE_IT_RISING;
  GPIO_InitStruct.Pull = GPIO_NOPULL;
  HAL_GPIO_Init(MFX_IRQOUT_GPIO_Port, &GPIO_InitStruct);

  /*Configure GPIO pin : MCO_Pin */
  GPIO_InitStruct.Pin = MCO_Pin;
  GPIO_InitStruct.Mode = GPIO_MODE_AF_PP;
  GPIO_InitStruct.Pull = GPIO_NOPULL;
  GPIO_InitStruct.Speed = GPIO_SPEED_FREQ_LOW;
  GPIO_InitStruct.Alternate = GPIO_AF0_MCO;
  HAL_GPIO_Init(MCO_GPIO_Port, &GPIO_InitStruct);

  /*Configure GPIO pin : ULPI_DIR_Pin */
  GPIO_InitStruct.Pin = ULPI_DIR_Pin;
  GPIO_InitStruct.Mode = GPIO_MODE_AF_PP;
  GPIO_InitStruct.Pull = GPIO_NOPULL;
  GPIO_InitStruct.Speed = GPIO_SPEED_FREQ_HIGH;
  GPIO_InitStruct.Alternate = GPIO_AF10_OTG2_HS;
  HAL_GPIO_Init(ULPI_DIR_GPIO_Port, &GPIO_InitStruct);

  /*Configure GPIO pin : SAI1_MCLKA_Pin */
  GPIO_InitStruct.Pin = SAI1_MCLKA_Pin;
  GPIO_InitStruct.Mode = GPIO_MODE_AF_PP;
  GPIO_InitStruct.Pull = GPIO_NOPULL;
  GPIO_InitStruct.Speed = GPIO_SPEED_FREQ_LOW;
  GPIO_InitStruct.Alternate = GPIO_AF6_SAI1;
  HAL_GPIO_Init(SAI1_MCLKA_GPIO_Port, &GPIO_InitStruct);

  /*Configure GPIO pins : A2_Pin A1_Pin A0_Pin A3_Pin
                           A4_Pin A7_Pin A8_Pin A6_Pin
                           A9_Pin SNDRAS_Pin */
  GPIO_InitStruct.Pin = A2_Pin|A1_Pin|A0_Pin|A3_Pin
                          |A4_Pin|A7_Pin|A8_Pin|A6_Pin
                          |A9_Pin|SNDRAS_Pin;
  GPIO_InitStruct.Mode = GPIO_MODE_AF_PP;
  GPIO_InitStruct.Pull = GPIO_NOPULL;
  GPIO_InitStruct.Speed = GPIO_SPEED_FREQ_VERY_HIGH;
  GPIO_InitStruct.Alternate = GPIO_AF12_FMC;
  HAL_GPIO_Init(GPIOF, &GPIO_InitStruct);

  /*Configure GPIO pin : QSPI_BK1_NCS_Pin */
  GPIO_InitStruct.Pin = QSPI_BK1_NCS_Pin;
  GPIO_InitStruct.Mode = GPIO_MODE_AF_PP;
  GPIO_InitStruct.Pull = GPIO_NOPULL;
  GPIO_InitStruct.Speed = GPIO_SPEED_FREQ_LOW;
  GPIO_InitStruct.Alternate = GPIO_AF10_QUADSPI;
  HAL_GPIO_Init(QSPI_BK1_NCS_GPIO_Port, &GPIO_InitStruct);

  /*Configure GPIO pins : LCD_HSYNC_Pin LCD_VSYNC_Pin LCD_CLK_Pin LCD_R0_Pin */
  GPIO_InitStruct.Pin = LCD_HSYNC_Pin|LCD_VSYNC_Pin|LCD_CLK_Pin|LCD_R0_Pin;
  GPIO_InitStruct.Mode = GPIO_MODE_AF_PP;
  GPIO_InitStruct.Pull = GPIO_NOPULL;
  GPIO_InitStruct.Speed = GPIO_SPEED_FREQ_LOW;
  GPIO_InitStruct.Alternate = GPIO_AF14_LTDC;
  HAL_GPIO_Init(GPIOI, &GPIO_InitStruct);

  /*Configure GPIO pin : PF5 */
  GPIO_InitStruct.Pin = GPIO_PIN_5;
  GPIO_InitStruct.Mode = GPIO_MODE_IT_RISING;
  GPIO_InitStruct.Pull = GPIO_NOPULL;
  HAL_GPIO_Init(GPIOF, &GPIO_InitStruct);

  /*Configure GPIO pins : QSPI_BK1_IO3_Pin QSPI_BK1_IO2_Pin */
  GPIO_InitStruct.Pin = QSPI_BK1_IO3_Pin|QSPI_BK1_IO2_Pin;
  GPIO_InitStruct.Mode = GPIO_MODE_AF_PP;
  GPIO_InitStruct.Pull = GPIO_NOPULL;
  GPIO_InitStruct.Speed = GPIO_SPEED_FREQ_LOW;
  GPIO_InitStruct.Alternate = GPIO_AF9_QUADSPI;
  HAL_GPIO_Init(GPIOF, &GPIO_InitStruct);

  /*Configure GPIO pins : QSPI_BK1_IO0_Pin QSPI_BK1_IO1_Pin */
  GPIO_InitStruct.Pin = QSPI_BK1_IO0_Pin|QSPI_BK1_IO1_Pin;
  GPIO_InitStruct.Mode = GPIO_MODE_AF_PP;
  GPIO_InitStruct.Pull = GPIO_NOPULL;
  GPIO_InitStruct.Speed = GPIO_SPEED_FREQ_LOW;
  GPIO_InitStruct.Alternate = GPIO_AF10_QUADSPI;
  HAL_GPIO_Init(GPIOF, &GPIO_InitStruct);

  /*Configure GPIO pin : ULPI_STP_Pin */
  GPIO_InitStruct.Pin = ULPI_STP_Pin;
  GPIO_InitStruct.Mode = GPIO_MODE_AF_PP;
  GPIO_InitStruct.Pull = GPIO_NOPULL;
  GPIO_InitStruct.Speed = GPIO_SPEED_FREQ_HIGH;
  GPIO_InitStruct.Alternate = GPIO_AF10_OTG2_HS;
  HAL_GPIO_Init(ULPI_STP_GPIO_Port, &GPIO_InitStruct);

  /*Configure GPIO pin : LED1_RGB_Pin */
  GPIO_InitStruct.Pin = LED2_Pin;
  GPIO_InitStruct.Mode = GPIO_MODE_OUTPUT_PP;
  GPIO_InitStruct.Pull = GPIO_NOPULL;
  GPIO_InitStruct.Speed = GPIO_SPEED_FREQ_LOW;
  HAL_GPIO_Init(LED2_GPIO_Port, &GPIO_InitStruct);

  /*Configure GPIO pins : RMII_MDC_Pin RMII_RXD0_Pin RMII_RXD1_Pin */
  GPIO_InitStruct.Pin = RMII_MDC_Pin|RMII_RXD0_Pin|RMII_RXD1_Pin;
  GPIO_InitStruct.Mode = GPIO_MODE_AF_PP;
  GPIO_InitStruct.Pull = GPIO_NOPULL;
  GPIO_InitStruct.Speed = GPIO_SPEED_FREQ_LOW;
  GPIO_InitStruct.Alternate = GPIO_AF11_ETH;
  HAL_GPIO_Init(GPIOC, &GPIO_InitStruct);

  /*Configure GPIO pin : DFSDM_CLK_Pin */
  GPIO_InitStruct.Pin = DFSDM_CLK_Pin;
  GPIO_InitStruct.Mode = GPIO_MODE_AF_PP;
  GPIO_InitStruct.Pull = GPIO_NOPULL;
  GPIO_InitStruct.Speed = GPIO_SPEED_FREQ_LOW;
  GPIO_InitStruct.Alternate = GPIO_AF6_DFSDM1;
  HAL_GPIO_Init(DFSDM_CLK_GPIO_Port, &GPIO_InitStruct);

  /*Configure GPIO pin : DFSM_DAT1_Pin */
  GPIO_InitStruct.Pin = DFSM_DAT1_Pin;
  GPIO_InitStruct.Mode = GPIO_MODE_AF_PP;
  GPIO_InitStruct.Pull = GPIO_NOPULL;
  GPIO_InitStruct.Speed = GPIO_SPEED_FREQ_LOW;
  GPIO_InitStruct.Alternate = GPIO_AF3_DFSDM1;
  HAL_GPIO_Init(DFSM_DAT1_GPIO_Port, &GPIO_InitStruct);

  /*Configure GPIO pins : QSPI_BK2_IO0_Pin QSPI_BK2_IO1_Pin */
  GPIO_InitStruct.Pin = QSPI_BK2_IO0_Pin|QSPI_BK2_IO1_Pin;
  GPIO_InitStruct.Mode = GPIO_MODE_AF_PP;
  GPIO_InitStruct.Pull = GPIO_NOPULL;
  GPIO_InitStruct.Speed = GPIO_SPEED_FREQ_LOW;
  GPIO_InitStruct.Alternate = GPIO_AF9_QUADSPI;
  HAL_GPIO_Init(GPIOH, &GPIO_InitStruct);

  /*Configure GPIO pins : ETH_MDIO_Pin RMII_REF_CLK_Pin RMII_CRS_DV_Pin */
  GPIO_InitStruct.Pin = ETH_MDIO_Pin|RMII_REF_CLK_Pin|RMII_CRS_DV_Pin;
  GPIO_InitStruct.Mode = GPIO_MODE_AF_PP;
  GPIO_InitStruct.Pull = GPIO_NOPULL;
  GPIO_InitStruct.Speed = GPIO_SPEED_FREQ_LOW;
  GPIO_InitStruct.Alternate = GPIO_AF11_ETH;
  HAL_GPIO_Init(GPIOA, &GPIO_InitStruct);

  /*Configure GPIO pin : ULPI_NXT_Pin */
  GPIO_InitStruct.Pin = ULPI_NXT_Pin;
  GPIO_InitStruct.Mode = GPIO_MODE_AF_PP;
  GPIO_InitStruct.Pull = GPIO_NOPULL;
  GPIO_InitStruct.Speed = GPIO_SPEED_FREQ_HIGH;
  GPIO_InitStruct.Alternate = GPIO_AF10_OTG2_HS;
  HAL_GPIO_Init(ULPI_NXT_GPIO_Port, &GPIO_InitStruct);

  /*Configure GPIO pin : QSPI_CLK_Pin */
  GPIO_InitStruct.Pin = QSPI_CLK_Pin;
  GPIO_InitStruct.Mode = GPIO_MODE_AF_PP;
  GPIO_InitStruct.Pull = GPIO_NOPULL;
  GPIO_InitStruct.Speed = GPIO_SPEED_FREQ_LOW;
  GPIO_InitStruct.Alternate = GPIO_AF9_QUADSPI;
  HAL_GPIO_Init(QSPI_CLK_GPIO_Port, &GPIO_InitStruct);

  /*Configure GPIO pins : ULPI_CK_Pin ULPI_D0_Pin */
  GPIO_InitStruct.Pin = ULPI_CK_Pin|ULPI_D0_Pin;
  GPIO_InitStruct.Mode = GPIO_MODE_AF_PP;
  GPIO_InitStruct.Pull = GPIO_NOPULL;
  GPIO_InitStruct.Speed = GPIO_SPEED_FREQ_HIGH;
  GPIO_InitStruct.Alternate = GPIO_AF10_OTG2_HS;
  HAL_GPIO_Init(GPIOA, &GPIO_InitStruct);

  /*Configure GPIO pins : RS_232RX_Pin RS232_TX_Pin */
  GPIO_InitStruct.Pin = RS_232RX_Pin|RS232_TX_Pin;
  GPIO_InitStruct.Mode = GPIO_MODE_AF_PP;
  GPIO_InitStruct.Pull = GPIO_NOPULL;
  GPIO_InitStruct.Speed = GPIO_SPEED_FREQ_LOW;
  GPIO_InitStruct.Alternate = GPIO_AF4_USART1;
  HAL_GPIO_Init(GPIOB, &GPIO_InitStruct);

  GPIO_InitStruct.Pin = SD_DETECT_Pin;
  GPIO_InitStruct.Mode = GPIO_MODE_IT_RISING_FALLING;
  GPIO_InitStruct.Pull = GPIO_PULLUP;
  HAL_GPIO_Init(SD_DETECT_GPIO_Port, &GPIO_InitStruct);

  /*AnalogSwitch Config */
  HAL_SYSCFG_AnalogSwitchConfig(SYSCFG_SWITCH_PA0, SYSCFG_SWITCH_PA0_OPEN);

  /* EXTI interrupt init*/
  HAL_NVIC_SetPriority(EXTI9_5_IRQn, 6, 0);
  HAL_NVIC_EnableIRQ(EXTI9_5_IRQn);

}

/* MPU Configuration */

void MPU_Config(void)
{
  MPU_Region_InitTypeDef MPU_InitStruct = {0};

  /* Disables the MPU */
  HAL_MPU_Disable();

  /** Initializes and configures the Region and the memory to be protected
  */
  MPU_InitStruct.Enable = MPU_REGION_ENABLE;
  MPU_InitStruct.Number = MPU_REGION_NUMBER0;
  MPU_InitStruct.BaseAddress = 0x0;
  MPU_InitStruct.Size = MPU_REGION_SIZE_4GB;
  MPU_InitStruct.SubRegionDisable = 0x87;
  MPU_InitStruct.TypeExtField = MPU_TEX_LEVEL0;
  MPU_InitStruct.AccessPermission = MPU_REGION_NO_ACCESS;
  MPU_InitStruct.DisableExec = MPU_INSTRUCTION_ACCESS_DISABLE;
  MPU_InitStruct.IsShareable = MPU_ACCESS_SHAREABLE;
  MPU_InitStruct.IsCacheable = MPU_ACCESS_NOT_CACHEABLE;
  MPU_InitStruct.IsBufferable = MPU_ACCESS_NOT_BUFFERABLE;

  HAL_MPU_ConfigRegion(&MPU_InitStruct);
  /* Enables the MPU */
  HAL_MPU_Enable(MPU_PRIVILEGED_DEFAULT);

}

void HAL_TIM_PeriodElapsedCallback(TIM_HandleTypeDef *htim)
{
  if (htim->Instance == TIM6) {
    HAL_IncTick();
  }
}

void Error_Handler(void)
{
  __disable_irq();
  while (1)
  {
  }
}
